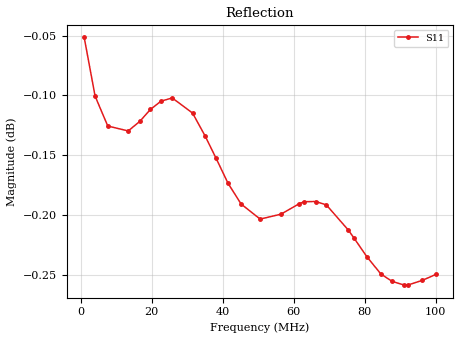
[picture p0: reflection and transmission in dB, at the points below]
# MHz S RI R 50.0
! SimSmith 18.4g
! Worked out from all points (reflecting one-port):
!   1000 points, 1 MHz to 100 MHz, reference 50 ohm
!   lowest |S11| = -0.3 dB at 91.18 MHz (marker M1), VSWR 67.21, Z = 2.6 + j79 ohm
!   phase of S11 starts at 171 deg and turns -906 deg over the sweep
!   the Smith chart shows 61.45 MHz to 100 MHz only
!   S11 on the Smith chart (normalised r, x): 61.45 MHz: 0.27, -4.87; 69.18 MHz: 0.02, -0.94; 76.91 MHz: 0.01, -0.13; 84.54 MHz: 0.02, +0.52; 92.27 MHz: 0.07, +1.93; 100 MHz: 0.74, -7.05
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1  -0.9805 0.1638
4.072072  -0.78 0.6072
7.63964  -0.3259 0.9302
13.38739  0.5406 0.8236
16.65766  0.8796 0.4457
19.63063  0.9872 -0.0043
22.6036  0.8773 -0.4544
25.77478  0.5475 -0.8228
31.52252  -0.3213 -0.9331
35.09009  -0.7732 -0.6097
38.16216  -0.9675 -0.1714
41.53153  -0.9157 0.3497
45.1982  -0.5674 0.7969
50.54955  0.2291 0.9496
56.3964  0.8996 0.3819
61.45045  0.8995 -0.3846
62.93694  0.7842 -0.5852
66.20721  0.3882 -0.8982
69.18018  -0.0653 -0.976
75.32432  -0.8462 -0.486
76.90991  -0.9404 -0.2578
80.57658  -0.9241 0.3056
84.54054  -0.5624 0.7924
87.71171  -0.1069 0.9651
91.18018  0.4164 0.8768
92.27027  0.5619 0.7915
96.23423  0.9214 0.3067
100  0.9341 -0.2675
